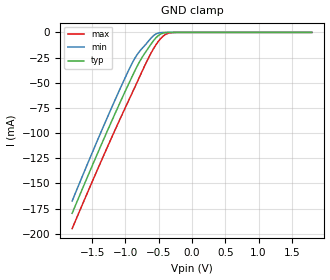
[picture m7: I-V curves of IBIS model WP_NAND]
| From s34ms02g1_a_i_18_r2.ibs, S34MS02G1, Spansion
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|   Model WP_NAND
[Model]   WP_NAND
Model_type   Input
Vinl = 0.360V
Vinh = 1.440V
| variable   typ   min   max
C_comp   2.20pF   1.98pF   2.64pF
| variable   typ   min   max
[Temperature Range]  25.00   -30.00   85.00
[Voltage Range]   1.800   1.700   1.950
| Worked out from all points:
|   GND clamp passes 1 mA (typ) near -0.44 V on its own axis
[GND_clamp]
| voltage   I(typ)   I(min)   I(max)
-1.8V     -179.7mA   -167.5mA   -194.9mA
-1.296V   -101.6mA   -88.27mA   -117.7mA
-1.08V    -69.66mA   -56.04mA   -86.04mA
-900mV    -44.03mA   -30.78mA   -60.39mA
-828mV    -34.24mA   -22.53mA   -50.11mA
-756mV    -25.57mA   -16.42mA   -39.72mA
-612mV    -11.34mA   -5.433mA   -20.24mA
-504mV    -3.112mA   -584.9uA   -8.784mA
-432mV    -702.1uA   -55.32uA   -3.659mA
-360mV    -93.96uA   -2.943uA   -1.018mA
-252mV    -2.155uA   -17.44nA   -71.48uA
1.8V      140.8pA    79.27pA    15.93nA
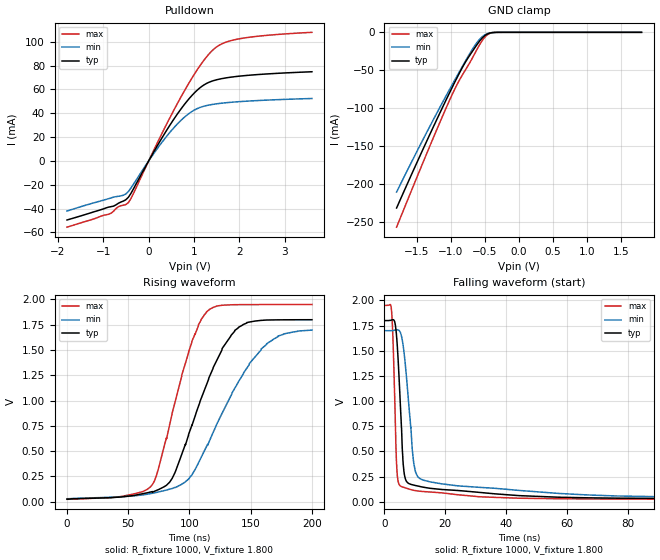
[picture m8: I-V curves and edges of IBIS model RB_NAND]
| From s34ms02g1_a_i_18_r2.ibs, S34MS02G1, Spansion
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|   Model RB_NAND
[Model]   RB_NAND
Model_type   Open_drain
Vmeas  = 0.100V
Vref   = 1.800V
Rref   = 1000
Cref   = 30pF
| variable   typ   min   max
C_comp   3.28pF   2.95pF   3.94pF
| variable   typ   min   max
[Temperature Range]  25.00   85.00   -30.00
[Voltage Range]   1.800   1.700   1.950
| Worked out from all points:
|   slope of the pulldown table from 0 to 0.27 V, typ, clamps not added: 15.1 ohm
|   GND clamp passes 1 mA (typ) near -0.43 V on its own axis
|   rising waveform, R_fixture 1000, V_fixture 1.800: 20-80 % time 33.2ns typ, 42.3ns min, 25.2ns max; typ from 0.026 V to 1.8 V
|   falling waveform, R_fixture 1000, V_fixture 1.800: 20-80 % time 1.71ns typ, 2.89ns min, 1.07ns max; typ from 1.8 V to 0.027 V
[Pulldown]
| voltage   I(typ)   I(min)   I(max)
-1.8V     -49.57mA   -42.06mA   -55.58mA
-882mV    -38.77mA   -31.65mA   -44.75mA
-666mV    -35.48mA   -29.65mA   -38.38mA
-558mV    -33.68mA   -28.8mA    -37.15mA
-450mV    -30.63mA   -25.76mA   -35.12mA
198mV     13.22mA    10.77mA    15.71mA
630mV     39.23mA    30.9mA     47.96mA
1.062V    59.12mA    43.78mA    76.02mA
1.44V     67.51mA    47.63mA    93.97mA
1.656V    69.39mA    48.66mA    98.99mA
2.034V    71.29mA    49.86mA    102.8mA
3.6V      74.86mA    52.41mA    108mA
[GND_clamp]
| voltage   I(typ)   I(min)   I(max)
-1.8V     -231.2mA   -210.2mA   -256.4mA
-1.296V   -131.4mA   -121.2mA   -146.5mA
-1.116V   -97.16mA   -90.8mA    -108.6mA
-972mV    -70.56mA   -67.2mA    -79.79mA
-900mV    -57.7mA    -55.62mA   -66.75mA
-792mV    -39.77mA   -38.44mA   -50.05mA
-648mV    -20.03mA   -17.09mA   -27.44mA
-540mV    -7.347mA   -5.7mA     -10.68mA
-468mV    -2.257mA   -1.767mA   -3.355mA
-396mV    -382.9uA   -351.7uA   -517uA
-324mV    -40.44uA   -51.26uA   -40.69uA
1.8V      234.3pA    1.661nA    138.6pA
[Ramp]
| variable   typ   min   max
dV/dt_r   1.06/31.68n   999.89m/40.91n   1.16/24.25n
dV/dt_f   1.06/1.71n   1.00/2.86n   1.16/1.07n
R_load = 50
[Rising Waveform]
R_fixture   = 1000
V_fixture   = 1.800
V_fixture_min = 1.700
V_fixture_max = 1.950
| time   V(typ)   V(min)   V(max)
0s        26.01mV    29.8mV     23.95mV
44.68ns   47.9mV     49.87mV    53.02mV
69.73ns   100.6mV    83.7mV     170.1mV
85.82ns   230.2mV    130.8mV    874.4mV
101.9ns   754.6mV    265mV      1.585V
116.2ns   1.233V     596.8mV    1.902V
136.9ns   1.692V     1.12V      1.948V
158.5ns   1.792V     1.509V     1.949V
176.9ns   1.798V     1.659V     1.949V
200ns     1.799V     1.696V     1.95V
[Falling Waveform]
R_fixture   = 1000
V_fixture   = 1.800
V_fixture_min = 1.700
V_fixture_max = 1.950
| time   V(typ)   V(min)   V(max)
0s        1.8V       1.7V       1.95V
2.376ns   1.806V     1.7V       1.894V
2.88ns    1.809V     1.702V     1.573V
3.96ns    1.664V     1.707V     408.7mV
4.392ns   1.481V     1.708V     227.4mV
6.192ns   372.8mV    1.547V     144.9mV
8.1ns     180mV      938.4mV    126mV
10.58ns   159.1mV    270.4mV    108.9mV
18.9ns    121.7mV    177.7mV    88.29mV
200ns     26.9mV     32.49mV    24.19mV
